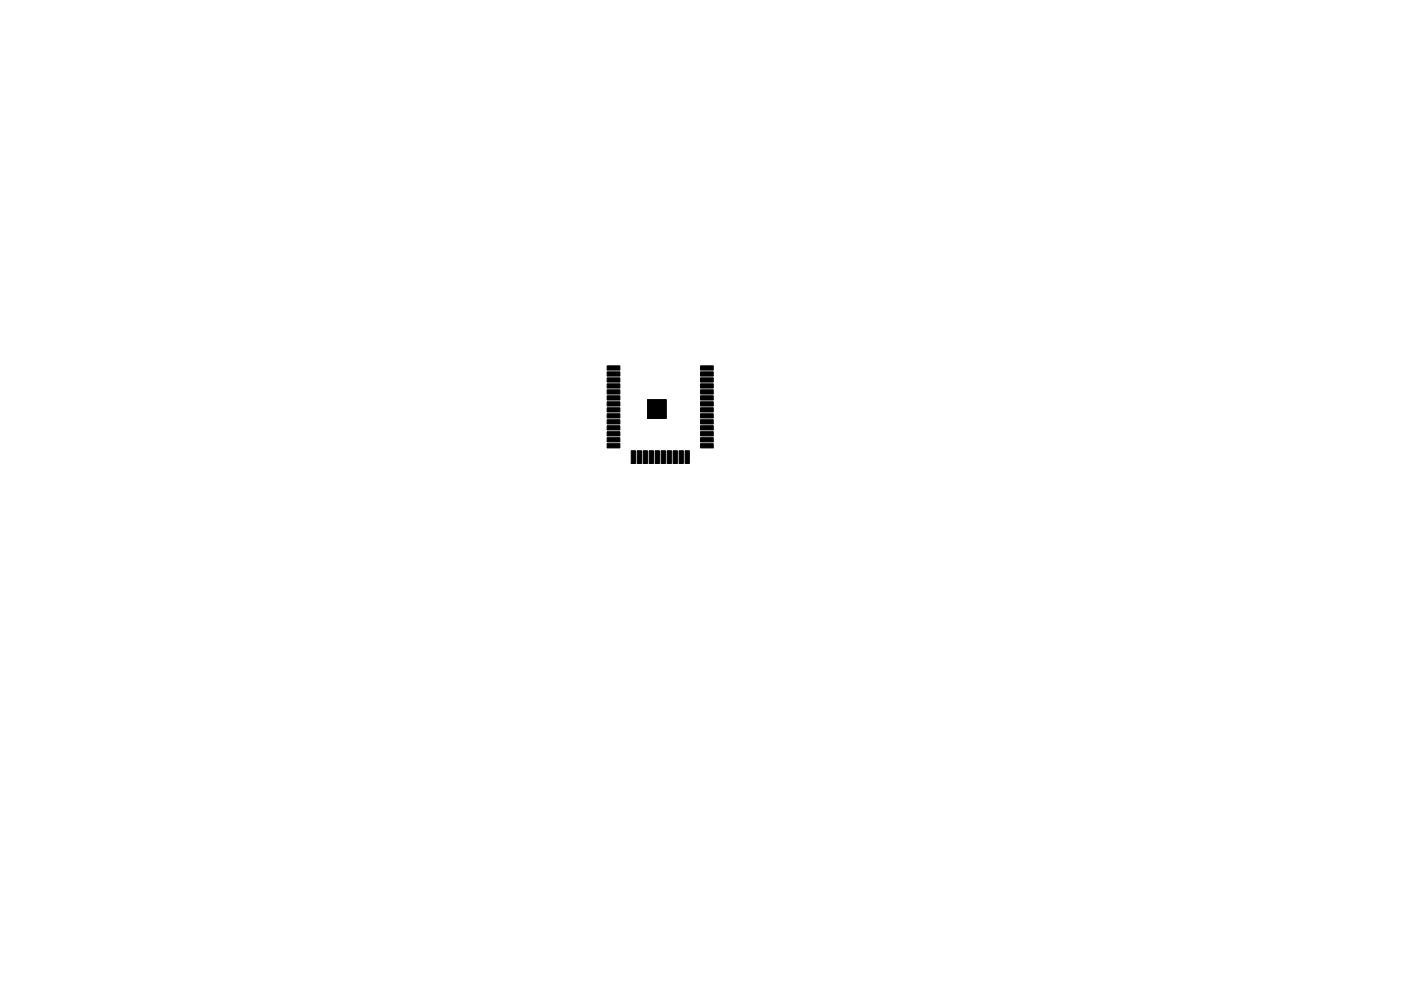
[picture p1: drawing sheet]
<svg xmlns="http://www.w3.org/2000/svg" width="297mm" height="210mm" viewBox="0 0 297 210" stroke-linecap="round" stroke-linejoin="round" font-family="sans-serif">
<g fill="#000" stroke="#000" stroke-width=".21">
<path d="M128.7 78.9h2.7v.9h-2.7zM128.7 77.6h2.7v.9h-2.7zM148.5 78.9h2.7v.9h-2.7zM148.5 77.6h2.7v.9h-2.7zM128.7 94.1h2.7v.9h-2.7zM128.7 92.9h2.7v.9h-2.7zM128.7 91.6h2.7v.9h-2.7zM128.7 90.3h2.7v.9h-2.7zM128.7 89.1h2.7v.9h-2.7zM128.7 87.8h2.7v.9h-2.7zM128.7 86.5h2.7v.9h-2.7zM128.7 85.2h2.7v.9h-2.7z"/>
<path d="M128.7 84h2.7v.9h-2.7zM128.7 82.7h2.7v.9h-2.7zM128.7 81.4h2.7v.9h-2.7zM128.7 80.2h2.7v.9h-2.7zM133.8 95.6h.9v2.7h-.9zM135.1 95.6h.9v2.7h-.9zM136.4 95.6h.9v2.7h-.9zM137.3 84.8h4v4h-4zM137.6 95.6h.9v2.7h-.9zM138.9 95.6h.9v2.7h-.9zM140.2 95.6h.9v2.7h-.9zM141.4 95.6h.9v2.7h-.9z"/>
<path d="M142.7 95.6h.9v2.7h-.9zM144 95.6h.9v2.7h-.9zM145.3 95.6h.9v2.7h-.9zM148.5 94.1h2.7v.9h-2.7zM148.5 92.9h2.7v.9h-2.7zM148.5 91.6h2.7v.9h-2.7zM148.5 90.3h2.7v.9h-2.7zM148.5 89.1h2.7v.9h-2.7zM148.5 87.8h2.7v.9h-2.7zM148.5 86.5h2.7v.9h-2.7zM148.5 85.2h2.7v.9h-2.7zM148.5 84h2.7v.9h-2.7z"/>
<path d="M148.5 82.7h2.7v.9h-2.7zM148.5 81.4h2.7v.9h-2.7zM148.5 80.2h2.7v.9h-2.7z"/>
</g>
</svg>
